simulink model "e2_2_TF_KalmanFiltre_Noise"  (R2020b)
settings: Solver=ode4  StartTime=0.0  StopTime=100  FixedStep=sampleTime  RelTol=1e-3  EnableMultiTasking=on
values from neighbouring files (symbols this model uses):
  gain_noise = 0.25    [startSimulation.m]
  k_d_x = 0.7    [startSimulation.m]
  k_d_y = 0.7    [startSimulation.m]
  k_d_yaw = 0.05    [startSimulation.m]
  k_d_z = 0.05    [startSimulation.m]
  k_i_x = 0.01    [startSimulation.m]
  k_i_y = 0.01    [startSimulation.m]
  k_i_yaw = 0.01    [startSimulation.m]
  k_i_z = 0.01    [startSimulation.m]
  k_p_x = 1    [startSimulation.m]
  k_p_y = 1    [startSimulation.m]
  k_p_yaw = 2    [startSimulation.m]
  k_p_z = 3    [startSimulation.m]
  saturation_psi = 2    [startSimulation.m]
  saturation_x = 2    [startSimulation.m]
  saturation_y = 2    [startSimulation.m]
  saturation_z = 2    [startSimulation.m]
  simDT = 0.01    [startSimulation.m]
undefined symbols (not defined in the file or in its folder): DiscIntNeverNeededParam, KiRollAttitude, sigbuilder_block, unidrnd
libraries: simulink x12, pid_lib x2, aerolibanimutils x1

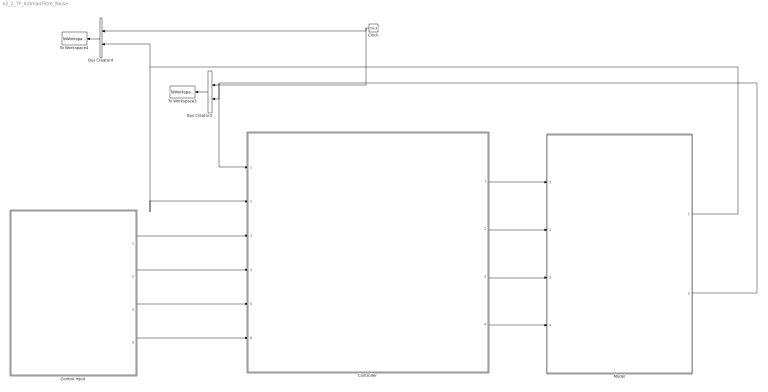
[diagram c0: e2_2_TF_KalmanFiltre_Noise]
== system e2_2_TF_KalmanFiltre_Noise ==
  Bus Creator3 : BusCreator  Inputs=2
  Bus Creator4 : BusCreator  Inputs=2
  Clock : Clock
  Control Input : Subsystem
  "Controller " : Subsystem
  Model : Subsystem
  To Workspace3 : ToWorkspace  VariableName=r1_pos_array  SampleTime=-1
  To Workspace4 : ToWorkspace  VariableName=r1_vel_array  SampleTime=-1
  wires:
  Clock/1 -> Bus Creator4/1, Bus Creator3/1
  Bus Creator3/1 -> To Workspace3/1
  Bus Creator4/1 -> To Workspace4/1
  "Controller "/1(Controller Output X) -> Model/1(Commande Input X)
  "Controller "/2(Controller Output Y) -> Model/2(Commande Input Y)
  "Controller "/3(Controller Output H) -> Model/3(Commande Input H)
  "Controller "/4(Controller Output Psi) -> Model/4(Commande Input Psi)
  Control Input/1(ux) -> "Controller "/3(Control input X)
  Control Input/2(uy) -> "Controller "/4(Control input Y)
  Control Input/3(uz) -> "Controller "/5(Control input H)
  Control Input/4(upsi) -> "Controller "/6(Control input Psi)
  Model/2(Output Position) -> "Controller "/1(Feedback Position), Bus Creator3/2
  Model/1(Output Velocity) -> "Controller "/2(Feedback Velocity), Bus Creator4/2

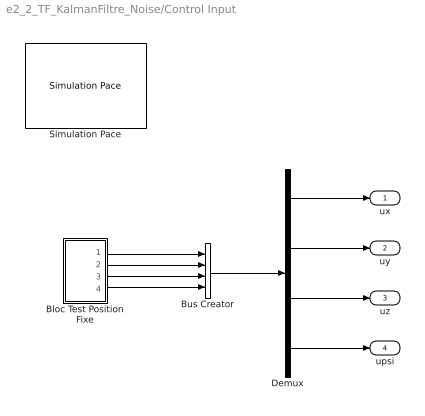
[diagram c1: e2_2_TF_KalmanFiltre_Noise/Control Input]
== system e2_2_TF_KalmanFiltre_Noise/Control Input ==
  Bloc Test Position Fixe : Subsystem
  Bus Creator : BusCreator  Inputs=4
  Demux : Demux
  Simulation Pace : aerolibanimutils/Simulation Pace  SimulationPace=100  SleepMode=MATLAB Thread  OutputPaceError=off  SampleTime=-1
  ux : Outport  VectorParamsAs1DForOutWhenUnconnected=off
  uy : Outport  Port=2  VectorParamsAs1DForOutWhenUnconnected=off
  uz : Outport  Port=3  VectorParamsAs1DForOutWhenUnconnected=off
  upsi : Outport  Port=4  VectorParamsAs1DForOutWhenUnconnected=off
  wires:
  Demux/2 -> uy/1
  Demux/1 -> ux/1
  Bloc Test Position Fixe/2(uy) -> Bus Creator/2
  Demux/3 -> uz/1
  Demux/4 -> upsi/1
  Bloc Test Position Fixe/4(upsi) -> Bus Creator/4
  Bloc Test Position Fixe/3(uz) -> Bus Creator/3
  Bloc Test Position Fixe/1(ux) -> Bus Creator/1
  Bus Creator/1 -> Demux/1

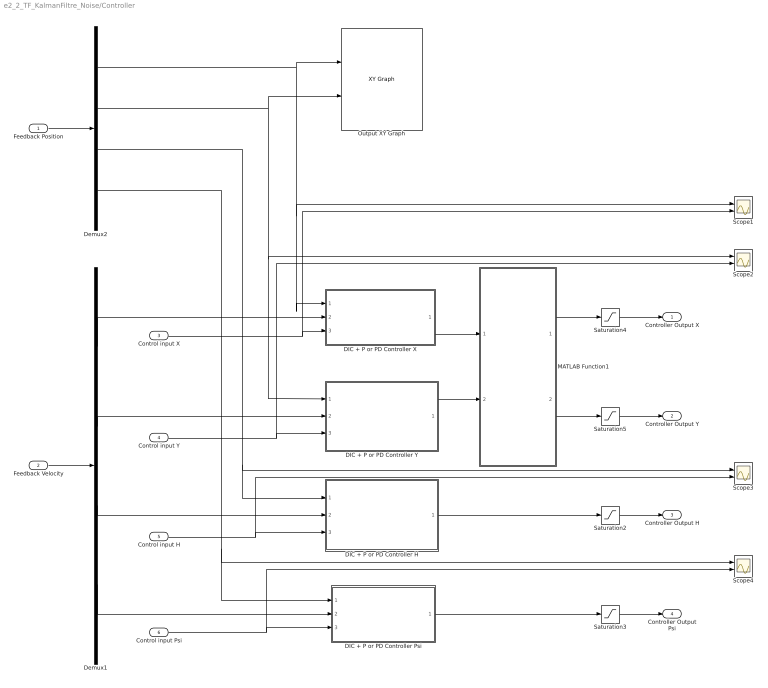
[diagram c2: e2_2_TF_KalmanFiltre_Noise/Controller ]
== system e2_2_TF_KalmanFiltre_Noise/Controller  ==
  Feedback Position : Inport
  Feedback Velocity : Inport  Port=2
  Control input X : Inport  Port=3
  Control input Y : Inport  Port=4
  Control input H : Inport  Port=5
  Control input Psi : Inport  Port=6
  DIC + P or PD Controller H : Subsystem
  DIC + P or PD Controller Psi : Subsystem
  DIC + P or PD Controller X : Subsystem
  DIC + P or PD Controller Y : Subsystem
  Demux1 : Demux
  Demux2 : Demux
  MATLAB Function1 : MATLAB Function  TreatAsAtomicUnit=on
  Output XY Graph : simulink/Sinks/XY Graph  Commented=on  xmin=-5  xmax=5  ymin=-5  ymax=5  st=-1
  Saturation2 : Saturate  UpperLimit=saturation_z  LowerLimit=-saturation_z
  Saturation3 : Saturate  UpperLimit=saturation_psi  LowerLimit=-saturation_psi
  Saturation4 : Saturate  UpperLimit=saturation_x  LowerLimit=-saturation_x
  Saturation5 : Saturate  UpperLimit=saturation_y  LowerLimit=-saturation_y
  Scope{1..4} (4 alike) : Scope  NumInputPorts=2
  Controller Output X : Outport  VectorParamsAs1DForOutWhenUnconnected=off
  Controller Output Y : Outport  Port=2  VectorParamsAs1DForOutWhenUnconnected=off
  Controller Output H : Outport  Port=3  VectorParamsAs1DForOutWhenUnconnected=off
  Controller Output Psi : Outport  Port=4  VectorParamsAs1DForOutWhenUnconnected=off
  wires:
  Feedback Position/1 -> Demux2/1
  Feedback Velocity/1 -> Demux1/1
  Demux1/2 -> DIC + P or PD Controller Y/2(Feedback Velocity Y)
  Demux2/3 -> Scope3/1, DIC + P or PD Controller H/1(Feedback Position H)
  Demux1/1 -> DIC + P or PD Controller X/2(Feedback Velocity X)
  Demux1/3 -> DIC + P or PD Controller H/2(Feedback Velocity H)
  Control input X/1 -> Scope1/2, DIC + P or PD Controller X/3(Control Input X)
  Control input H/1 -> Scope3/2, DIC + P or PD Controller H/3(Control Input H)
  Saturation4/1 -> Controller Output X/1
  Saturation5/1 -> Controller Output Y/1
  Saturation2/1 -> Controller Output H/1
  Saturation3/1 -> Controller Output Psi/1
  Control input Y/1 -> Scope2/2, DIC + P or PD Controller Y/3(Control Input Y)
  DIC + P or PD Controller H/1(Controller Output H) -> Saturation2/1
  DIC + P or PD Controller Psi/1(Controller Output Psi) -> Saturation3/1
  Demux2/1 -> Scope1/1, DIC + P or PD Controller X/1(Feedback Position X), Output XY Graph/1
  Demux2/2 -> Scope2/1, DIC + P or PD Controller Y/1(Feedback Position Y), Output XY Graph/2
  Demux2/4 -> Scope4/1, DIC + P or PD Controller Psi/1(Feedback Position Psi)
  Demux1/4 -> DIC + P or PD Controller Psi/2(Feedback Velocity Psi)
  Control input Psi/1 -> Scope4/2, DIC + P or PD Controller Psi/3(Control input Psi)
  MATLAB Function1/2(phi) -> Saturation5/1
  MATLAB Function1/1(theta) -> Saturation4/1
  DIC + P or PD Controller X/1(Controller Output X) -> MATLAB Function1/1(eax)
  DIC + P or PD Controller Y/1(Controller Output Y) -> MATLAB Function1/2(eay)

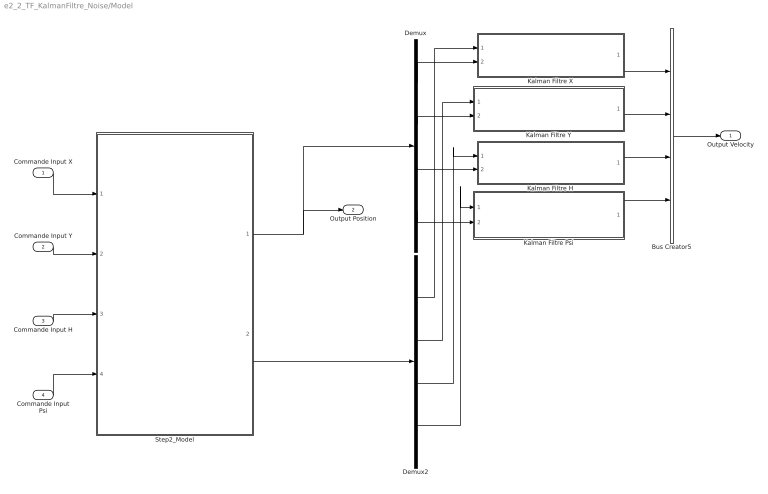
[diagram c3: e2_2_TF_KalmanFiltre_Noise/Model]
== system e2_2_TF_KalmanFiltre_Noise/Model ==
  Commande Input X : Inport
  Commande Input Y : Inport  Port=2
  Commande Input H : Inport  Port=3
  Commande Input Psi : Inport  Port=4
  Bus Creator5 : BusCreator  Inputs=4
  Demux : Demux
  Demux2 : Demux
  Kalman Filtre H : Subsystem
  Kalman Filtre Psi : Subsystem
  Kalman Filtre X : Subsystem
  Kalman Filtre Y : Subsystem
  Step2_Model : Subsystem
  Output Velocity : Outport  VectorParamsAs1DForOutWhenUnconnected=off
  Output Position : Outport  Port=2  VectorParamsAs1DForOutWhenUnconnected=off
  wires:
  Demux2/2 -> Kalman Filtre Y/1(The system output: Velocity)
  Demux/4 -> Kalman Filtre Psi/2(The system output: Position)
  Demux2/4 -> Kalman Filtre Psi/1(The system output: Velocity)
  Demux2/3 -> Kalman Filtre H/1(The system output: Velocity)
  Kalman Filtre H/1(Out velocity feedback) -> Bus Creator5/3
  Kalman Filtre Y/1(Out velocity feedback) -> Bus Creator5/2
  Kalman Filtre Psi/1(Out velocity feedback) -> Bus Creator5/4
  Demux/2 -> Kalman Filtre Y/2(The system output: Position)
  Demux2/1 -> Kalman Filtre X/1(The system output: Velocity)
  Kalman Filtre X/1(Out velocity feedback) -> Bus Creator5/1
  Demux/3 -> Kalman Filtre H/2(The system output: Position)
  Bus Creator5/1 -> Output Velocity/1
  Demux/1 -> Kalman Filtre X/2(The system output: Position)
  Commande Input H/1 -> Step2_Model/3(In3)
  Step2_Model/1(Position) -> Demux/1, Output Position/1
  Commande Input Psi/1 -> Step2_Model/4(In4)
  Commande Input X/1 -> Step2_Model/1(In1)
  Commande Input Y/1 -> Step2_Model/2(In2)
  Step2_Model/2(Velocity) -> Demux2/1

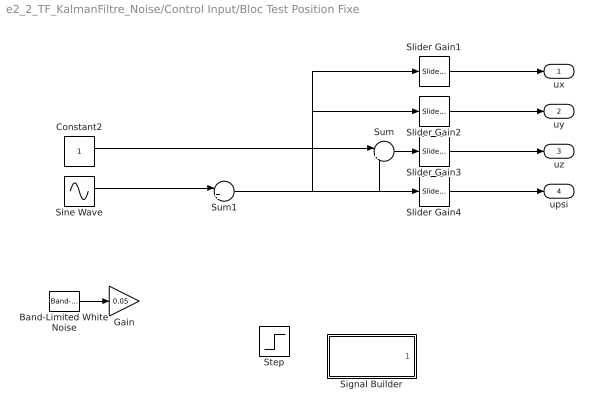
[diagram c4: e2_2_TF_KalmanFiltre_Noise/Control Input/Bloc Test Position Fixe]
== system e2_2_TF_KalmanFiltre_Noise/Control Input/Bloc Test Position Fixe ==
  Band-Limited White Noise : simulink/Sources/Band-Limited White Noise  Cov=[0.01]  Ts=simDT  seed=unidrnd(20000)
  Constant2 : Constant
  Gain : Gain  Gain=0.05
  Signal Builder : Subsystem  Tag=STV Subsys  LoadFcn=sigbuilder_block('load');  StartFcn=sigbuilder_block('start');  StopFcn=sigbuilder_block('stop');  ClipboardFcn=sigbuilder_block('clipboard');  mask(Sigbuilder block){tuvar=[0:10]}
      mask help: Simulink:masks:SigbuilderBlock_MD
      mask init:
      | if ~strcmp(get_param(bdroot(gcbh),'SimulationStatus'),'stopped') tuvar = sigbuilder_block('maskInit'); end
  Sine Wave : Sin  Frequency=0.3  SampleTime=0
  Slider Gain1 : simulink/Math Operations/Slider Gain  gain=1  low=-10  high=10
  Slider Gain2 : simulink/Math Operations/Slider Gain  gain=0  low=-10  high=10
  Slider Gain3 : simulink/Math Operations/Slider Gain  gain=1  low=-2  high=2
  Slider Gain4 : simulink/Math Operations/Slider Gain  gain=1  low=-2  high=2
  Step : Step  Time=5  SampleTime=0
  Sum : Sum  Inputs=|++
  Sum1 : Sum  Inputs=|++
  ux : Outport  VectorParamsAs1DForOutWhenUnconnected=off
  uy : Outport  Port=2  VectorParamsAs1DForOutWhenUnconnected=off
  uz : Outport  Port=3  VectorParamsAs1DForOutWhenUnconnected=off
  upsi : Outport  Port=4  VectorParamsAs1DForOutWhenUnconnected=off
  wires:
  Slider Gain1/1 -> ux/1
  Slider Gain2/1 -> uy/1
  Slider Gain3/1 -> uz/1
  Slider Gain4/1 -> upsi/1
  Sum/1 -> Slider Gain3/1
  Band-Limited White Noise/1 -> Gain/1
  Sine Wave/1 -> Sum1/1
  Sum1/1 -> Slider Gain1/1, Slider Gain2/1, Slider Gain4/1, Sum/2
  Constant2/1 -> Sum/1

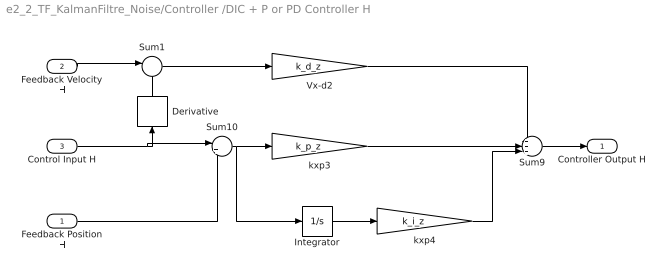
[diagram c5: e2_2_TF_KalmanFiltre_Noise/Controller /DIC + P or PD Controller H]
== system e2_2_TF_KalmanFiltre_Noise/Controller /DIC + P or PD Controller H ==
  Feedback Position H : Inport
  Feedback Velocity H : Inport  Port=2
  Control Input H : Inport  Port=3
  Derivative : Derivative
  Integrator : Integrator
  Sum1 : Sum  Inputs=|-+
  Sum10 : Sum  Inputs=|+-
  Sum9 : Sum  Inputs=+++|
  Vx-d2 : Gain  Gain=k_d_z
  kxp3 : Gain  Gain=k_p_z
  kxp4 : Gain  Gain=k_i_z
  Controller Output H : Outport  VectorParamsAs1DForOutWhenUnconnected=off
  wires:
  Sum9/1 -> Controller Output H/1
  Sum10/1 -> kxp3/1, Integrator/1
  kxp3/1 -> Sum9/2
  Vx-d2/1 -> Sum9/1
  Feedback Velocity H/1 -> Sum1/1
  Sum1/1 -> Vx-d2/1
  Integrator/1 -> kxp4/1
  kxp4/1 -> Sum9/3
  Control Input H/1 -> Sum10/1, Derivative/1
  Feedback Position H/1 -> Sum10/2
  Derivative/1 -> Sum1/2

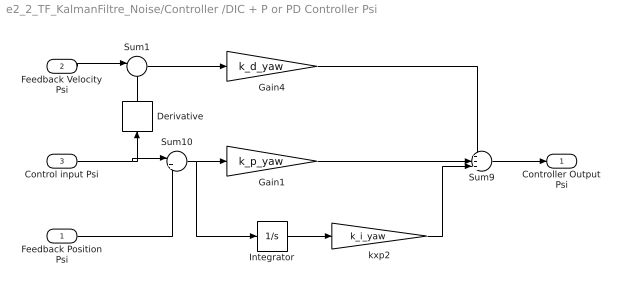
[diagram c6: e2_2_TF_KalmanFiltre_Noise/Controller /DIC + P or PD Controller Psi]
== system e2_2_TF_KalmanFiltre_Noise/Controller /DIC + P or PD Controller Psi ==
  Feedback Position Psi : Inport
  Feedback Velocity Psi : Inport  Port=2
  Control input Psi : Inport  Port=3
  Derivative : Derivative
  Gain1 : Gain  Gain=k_p_yaw
  Gain4 : Gain  Gain=k_d_yaw
  Integrator : Integrator
  Sum1 : Sum  Inputs=|-+
  Sum10 : Sum  Inputs=|+-
  Sum9 : Sum  Inputs=+++|
  kxp2 : Gain  Gain=k_i_yaw
  Controller Output Psi : Outport  VectorParamsAs1DForOutWhenUnconnected=off
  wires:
  Sum9/1 -> Controller Output Psi/1
  kxp2/1 -> Sum9/3
  Control input Psi/1 -> Sum10/1, Derivative/1
  Gain4/1 -> Sum9/1
  Sum10/1 -> Gain1/1, Integrator/1
  Integrator/1 -> kxp2/1
  Feedback Velocity Psi/1 -> Sum1/1
  Sum1/1 -> Gain4/1
  Gain1/1 -> Sum9/2
  Derivative/1 -> Sum1/2
  Feedback Position Psi/1 -> Sum10/2

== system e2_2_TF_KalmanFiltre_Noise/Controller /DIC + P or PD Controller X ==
  Feedback Position X : Inport
  Feedback Velocity X : Inport  Port=2
  Control Input X : Inport  Port=3
  PID1 : Subsystem
  Sum3 : Sum  Inputs=|+-
  Sum4 : Sum  Inputs=|+-
  roll_attitude2 : pid_lib/PID Controller  Controller=P  Form=Parallel  TimeDomain=Discrete-time  UseExternalTs=off  SampleTime=-1  IntegratorMethod=Forward Euler  FilterMethod=Forward Euler  ControllerParametersSource=internal  P=1  I=KiRollAttitude  D=0.01  UseFilter=on  N=100  TunerSelectOption=Transfer Function Based (PID Tuner App)  InitialConditionSource=internal  InitialConditionForIntegrator=0  InitialConditionForFilter=0  DifferentiatorICPrevScaledInput=0  ExternalReset=none  TrackingMode=off  Kt=1  LimitOutput=on  SatLimitsSource=internal  UpperSaturationLimit=100  LowerSaturationLimit=-100  LinearizeAsGain=on  AntiWindupMode=back-calculation  Kb=1  POutMin=[]  POutMax=[]  IOutMin=[]  IOutMax=[]  DOutMin=[]  DOutMax=[]  NOutMin=[]  NOutMax=[]  SumOutMin=[]  SumOutMax=[]  SaturationOutMin=[]  SaturationOutMax=[]  PParamMin=[]  PParamMax=[]  IParamMin=[]  IParamMax=[]  DParamMin=[]  DParamMax=[]  NParamMin=[]  NParamMax=[]  KbParamMin=[]  KbParamMax=[]  KtParamMin=[]  KtParamMax=[]  KbOutMin=[]  KbOutMax=[]  KtOutMin=[]  KtOutMax=[]  IntegratorOutMin=[]  IntegratorOutMax=[]  FilterOutMin=[]  FilterOutMax=[]  SumI1OutMin=[]  SumI1OutMax=[]  SumI2OutMin=[]  SumI2OutMax=[]  SumI3OutMin=[]  SumI3OutMax=[]  SumI4OutMin=[]  SumI4OutMax=[]  SumDOutMin=[]  SumDOutMax=[]  DifferentiatorOutMin=[]  DifferentiatorOutMax=[]  FilterDiffOutCoefMin=[]  FilterDiffOutCoefMax=[]  ReciprocalOutMin=[]  ReciprocalOutMax=[]  SumDenOutMin=[]  SumDenOutMax=[]  SumNumOutMin=[]  SumNumOutMax=[]  DivideOutMin=[]  DivideOutMax=[]  UdiffTsProdOutMin=[]  UdiffTsProdOutMax=[]  NTsProdOutMin=[]  NTsProdOutMax=[]  UintegralTsProdOutMin=[]  UintegralTsProdOutMax=[]  UngainTsProdOutMin=[]  UngainTsProdOutMax=[]  IntegratorContinuousStateAttributes=''  IntegratorStateMustResolveToSignalObject=off  IntegratorRTWStateStorageClass=Auto  FilterContinuousStateAttributes=''  FilterStateMustResolveToSignalObject=off  FilterRTWStateStorageClass=Auto  ParallelPVariant=InternalParameters  IdealPVariant=Disabled  IVariant=Disabled  DVariant=Disabled  IntegratorVariant=Disabled  SatVariant=Enabled  AWVariant=Disabled  PCopyVariant=Disabled  TRVariant=Disabled  FdbkBlocksVariant=Forward  IdealPFdbkVariant=Disabled  SatFdbkVariant=Disabled  DerivativeFilterVariant=Disabled  NVariant=Disabled  NCopyVariant=Disabled_SignalSpec  FilterICVariant=Disabled  IntegratorICVariant=Disabled  ExternalResetVariant=Disabled  TRSumVariant=Passthrough  SumFdbkVariant=Disabled  SumVariant=Passthrough_P  TsampFilterVariant=InternalTs  TsampNgainVariant=Passthrough  TsampIntegralVariant=Disabled_SignalSpec  ExternalSaturationOutDataTypeStr=Inherit: Same as second input
  Controller Output X : Outport  VectorParamsAs1DForOutWhenUnconnected=off
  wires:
  roll_attitude2/1 -> Sum4/1
  Sum3/1 -> roll_attitude2/1
  Sum4/1 -> PID1/1(x)
  PID1/1(y) -> Controller Output X/1
  Feedback Velocity X/1 -> Sum4/2
  Control Input X/1 -> Sum3/1
  Feedback Position X/1 -> Sum3/2

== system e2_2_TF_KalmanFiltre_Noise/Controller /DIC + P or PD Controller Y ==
  Feedback Position Y : Inport
  Feedback Velocity Y : Inport  Port=2
  Control Input Y : Inport  Port=3
  PID2 : Subsystem
  Sum : Sum  Inputs=|+-
  Sum2 : Sum  Inputs=|+-
  roll_attitude : pid_lib/PID Controller  Controller=P  Form=Parallel  TimeDomain=Discrete-time  UseExternalTs=off  SampleTime=-1  IntegratorMethod=Forward Euler  FilterMethod=Forward Euler  ControllerParametersSource=internal  P=1  I=KiRollAttitude  D=0.01  UseFilter=on  N=100  TunerSelectOption=Transfer Function Based (PID Tuner App)  InitialConditionSource=internal  InitialConditionForIntegrator=0  InitialConditionForFilter=0  DifferentiatorICPrevScaledInput=0  ExternalReset=none  TrackingMode=off  Kt=1  LimitOutput=on  SatLimitsSource=internal  UpperSaturationLimit=1  LowerSaturationLimit=-1  LinearizeAsGain=on  AntiWindupMode=back-calculation  Kb=1  POutMin=[]  POutMax=[]  IOutMin=[]  IOutMax=[]  DOutMin=[]  DOutMax=[]  NOutMin=[]  NOutMax=[]  SumOutMin=[]  SumOutMax=[]  SaturationOutMin=[]  SaturationOutMax=[]  PParamMin=[]  PParamMax=[]  IParamMin=[]  IParamMax=[]  DParamMin=[]  DParamMax=[]  NParamMin=[]  NParamMax=[]  KbParamMin=[]  KbParamMax=[]  KtParamMin=[]  KtParamMax=[]  KbOutMin=[]  KbOutMax=[]  KtOutMin=[]  KtOutMax=[]  IntegratorOutMin=[]  IntegratorOutMax=[]  FilterOutMin=[]  FilterOutMax=[]  SumI1OutMin=[]  SumI1OutMax=[]  SumI2OutMin=[]  SumI2OutMax=[]  SumI3OutMin=[]  SumI3OutMax=[]  SumI4OutMin=[]  SumI4OutMax=[]  SumDOutMin=[]  SumDOutMax=[]  DifferentiatorOutMin=[]  DifferentiatorOutMax=[]  FilterDiffOutCoefMin=[]  FilterDiffOutCoefMax=[]  ReciprocalOutMin=[]  ReciprocalOutMax=[]  SumDenOutMin=[]  SumDenOutMax=[]  SumNumOutMin=[]  SumNumOutMax=[]  DivideOutMin=[]  DivideOutMax=[]  UdiffTsProdOutMin=[]  UdiffTsProdOutMax=[]  NTsProdOutMin=[]  NTsProdOutMax=[]  UintegralTsProdOutMin=[]  UintegralTsProdOutMax=[]  UngainTsProdOutMin=[]  UngainTsProdOutMax=[]  IntegratorContinuousStateAttributes=''  IntegratorStateMustResolveToSignalObject=off  IntegratorRTWStateStorageClass=Auto  FilterContinuousStateAttributes=''  FilterStateMustResolveToSignalObject=off  FilterRTWStateStorageClass=Auto  ParallelPVariant=InternalParameters  IdealPVariant=Disabled  IVariant=Disabled  DVariant=Disabled  IntegratorVariant=Disabled  SatVariant=Enabled  AWVariant=Disabled  PCopyVariant=Disabled  TRVariant=Disabled  FdbkBlocksVariant=Forward  IdealPFdbkVariant=Disabled  SatFdbkVariant=Disabled  DerivativeFilterVariant=Disabled  NVariant=Disabled  NCopyVariant=Disabled_SignalSpec  FilterICVariant=Disabled  IntegratorICVariant=Disabled  ExternalResetVariant=Disabled  TRSumVariant=Passthrough  SumFdbkVariant=Disabled  SumVariant=Passthrough_P  TsampFilterVariant=InternalTs  TsampNgainVariant=Passthrough  TsampIntegralVariant=Disabled_SignalSpec  ExternalSaturationOutDataTypeStr=Inherit: Same as second input
  Controller Output Y : Outport  VectorParamsAs1DForOutWhenUnconnected=off
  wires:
  Sum/1 -> roll_attitude/1
  roll_attitude/1 -> Sum2/1
  Sum2/1 -> PID2/1(x)
  Feedback Position Y/1 -> Sum/2
  Feedback Velocity Y/1 -> Sum2/2
  Control Input Y/1 -> Sum/1
  PID2/1(y) -> Controller Output Y/1

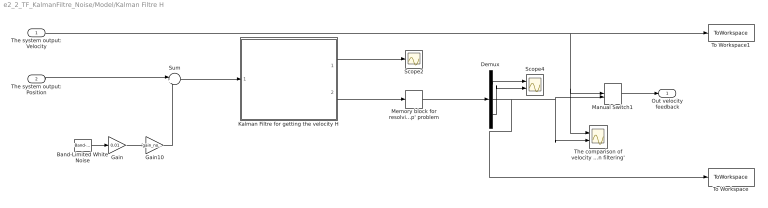
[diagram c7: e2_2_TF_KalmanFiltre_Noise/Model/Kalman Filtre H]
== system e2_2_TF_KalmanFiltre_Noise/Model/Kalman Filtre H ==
  The system output: Velocity : Inport
  The system output: Position : Inport  Port=2
  Band-Limited White Noise : simulink/Sources/Band-Limited White Noise  Cov=[0.01]  Ts=simDT  seed=unidrnd(20000)
  Demux : Demux  Outputs=3
  Gain : Gain  Gain=0.01
  Gain10 : Gain  Gain=gain_noise
  Kalman Filtre for getting the velocity H : MATLAB Function  TreatAsAtomicUnit=on  SystemSampleTime=0.01
  Manual Switch1 : ManualSwitch  CurrentSetting=0
  Memory block for resolving the 'algebraic loop' problem : Memory
  Scope2 : Scope
  Scope4 : Scope  NumInputPorts=2
  Sum : Sum  Inputs=|++
  The comparison of velocity signal between 'Derivative' and 'Kalman filtering' : Scope  NumInputPorts=2
  To Workspace : ToWorkspace  VariableName=vh_kalman  SampleTime=-1
  To Workspace1 : ToWorkspace  VariableName=vh_real  SampleTime=-1
  Out velocity feedback : Outport  VectorParamsAs1DForOutWhenUnconnected=off
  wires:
  Manual Switch1/1 -> Out velocity feedback/1
  Memory block for resolving the 'algebraic loop' problem/1 -> Demux/1
  Kalman Filtre for getting the velocity H/1(Covariance_matrice) -> Scope2/1
  Demux/1 -> Scope4/1
  Kalman Filtre for getting the velocity H/2(X_Kalmanfiltred) -> Memory block for resolving the 'algebraic loop' problem/1
  Demux/2 -> To Workspace/1, The comparison of velocity signal between 'Derivative' and 'Kalman filtering'/2, Manual Switch1/2
  Demux/3 -> Scope4/2
  The system output: Velocity/1 -> To Workspace1/1, The comparison of velocity signal between 'Derivative' and 'Kalman filtering'/1, Manual Switch1/1
  Gain10/1 -> Sum/2
  Band-Limited White Noise/1 -> Gain/1
  Gain/1 -> Gain10/1
  The system output: Position/1 -> Sum/1
  Sum/1 -> Kalman Filtre for getting the velocity H/1(Mesurement_Velocity)

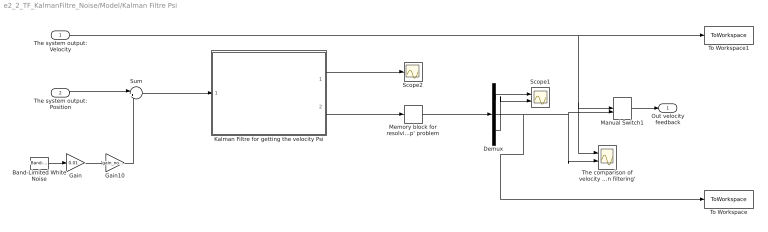
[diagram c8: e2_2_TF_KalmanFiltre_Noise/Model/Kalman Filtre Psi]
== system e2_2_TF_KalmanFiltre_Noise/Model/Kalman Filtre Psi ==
  The system output: Velocity : Inport
  The system output: Position : Inport  Port=2
  Band-Limited White Noise : simulink/Sources/Band-Limited White Noise  Cov=[0.01]  Ts=simDT  seed=unidrnd(20000)
  Demux : Demux  Outputs=3
  Gain : Gain  Gain=0.01
  Gain10 : Gain  Gain=gain_noise
  Kalman Filtre for getting the velocity Psi : MATLAB Function  TreatAsAtomicUnit=on  SystemSampleTime=0.01
  Manual Switch1 : ManualSwitch  CurrentSetting=0
  Memory block for resolving the 'algebraic loop' problem : Memory
  Scope1 : Scope  NumInputPorts=2
  Scope2 : Scope
  Sum : Sum  Inputs=|++
  The comparison of velocity signal between 'Derivative' and 'Kalman filtering' : Scope  NumInputPorts=2
  To Workspace : ToWorkspace  VariableName=vpsi_kalman  SampleTime=-1
  To Workspace1 : ToWorkspace  VariableName=vpsi_real  SampleTime=-1
  Out velocity feedback : Outport  VectorParamsAs1DForOutWhenUnconnected=off
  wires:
  Manual Switch1/1 -> Out velocity feedback/1
  Memory block for resolving the 'algebraic loop' problem/1 -> Demux/1
  Kalman Filtre for getting the velocity Psi/1(Covariance_matrice) -> Scope2/1
  Kalman Filtre for getting the velocity Psi/2(X_Kalmanfiltred) -> Memory block for resolving the 'algebraic loop' problem/1
  Demux/2 -> To Workspace/1, The comparison of velocity signal between 'Derivative' and 'Kalman filtering'/2, Manual Switch1/2
  Demux/1 -> Scope1/1
  Demux/3 -> Scope1/2
  The system output: Velocity/1 -> To Workspace1/1, The comparison of velocity signal between 'Derivative' and 'Kalman filtering'/1, Manual Switch1/1
  Sum/1 -> Kalman Filtre for getting the velocity Psi/1(Mesurement_Velocity)
  The system output: Position/1 -> Sum/1
  Gain10/1 -> Sum/2
  Band-Limited White Noise/1 -> Gain/1
  Gain/1 -> Gain10/1

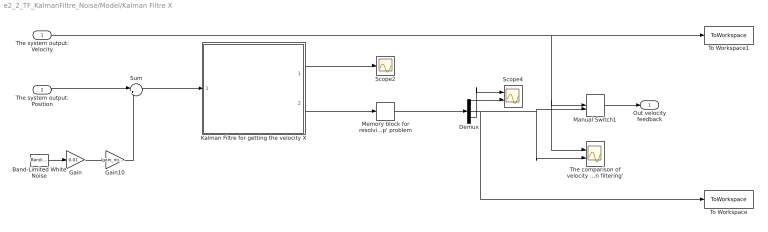
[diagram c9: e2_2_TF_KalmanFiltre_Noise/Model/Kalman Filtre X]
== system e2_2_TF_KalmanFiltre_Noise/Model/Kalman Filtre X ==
  The system output: Velocity : Inport
  The system output: Position : Inport  Port=2
  Band-Limited White Noise : simulink/Sources/Band-Limited White Noise  Cov=[0.01]  Ts=simDT  seed=unidrnd(20000)
  Demux : Demux  Outputs=3
  Gain : Gain  Gain=0.01
  Gain10 : Gain  Gain=gain_noise
  Kalman Filtre for getting the velocity X : MATLAB Function  TreatAsAtomicUnit=on  SystemSampleTime=0.01
  Manual Switch1 : ManualSwitch  CurrentSetting=0
  Memory block for resolving the 'algebraic loop' problem : Memory
  Scope2 : Scope
  Scope4 : Scope  NumInputPorts=2
  Sum : Sum  Inputs=|++
  The comparison of velocity signal between 'Derivative' and 'Kalman filtering' : Scope  NumInputPorts=2
  To Workspace : ToWorkspace  VariableName=vx_kalman  SampleTime=-1
  To Workspace1 : ToWorkspace  VariableName=vx_real  SampleTime=-1
  Out velocity feedback : Outport  VectorParamsAs1DForOutWhenUnconnected=off
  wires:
  Kalman Filtre for getting the velocity X/1(Covariance_matrice) -> Scope2/1
  Kalman Filtre for getting the velocity X/2(X_Kalmanfiltred) -> Memory block for resolving the 'algebraic loop' problem/1
  Memory block for resolving the 'algebraic loop' problem/1 -> Demux/1
  Manual Switch1/1 -> Out velocity feedback/1
  Demux/2 -> To Workspace/1, The comparison of velocity signal between 'Derivative' and 'Kalman filtering'/2, Manual Switch1/2
  Demux/1 -> Scope4/2
  Demux/3 -> Scope4/1
  The system output: Velocity/1 -> The comparison of velocity signal between 'Derivative' and 'Kalman filtering'/1, Manual Switch1/1, To Workspace1/1
  Gain10/1 -> Sum/2
  Band-Limited White Noise/1 -> Gain/1
  Gain/1 -> Gain10/1
  The system output: Position/1 -> Sum/1
  Sum/1 -> Kalman Filtre for getting the velocity X/1(Mesurement_Velocity)

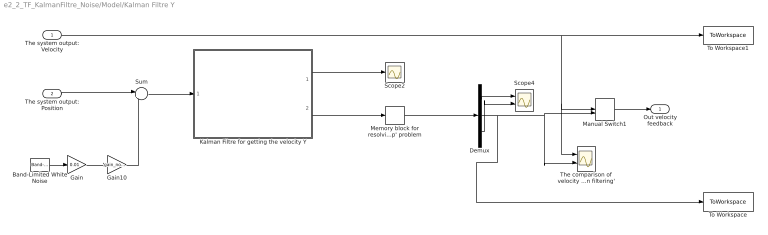
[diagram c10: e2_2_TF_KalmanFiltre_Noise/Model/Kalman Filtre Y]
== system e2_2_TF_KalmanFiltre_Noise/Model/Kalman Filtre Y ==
  The system output: Velocity : Inport
  The system output: Position : Inport  Port=2
  Band-Limited White Noise : simulink/Sources/Band-Limited White Noise  Cov=[0.01]  Ts=simDT  seed=unidrnd(20000)
  Demux : Demux  Outputs=3
  Gain : Gain  Gain=0.01
  Gain10 : Gain  Gain=gain_noise
  Kalman Filtre for getting the velocity Y : MATLAB Function  TreatAsAtomicUnit=on  SystemSampleTime=0.01
  Manual Switch1 : ManualSwitch  CurrentSetting=0
  Memory block for resolving the 'algebraic loop' problem : Memory
  Scope2 : Scope
  Scope4 : Scope  NumInputPorts=2
  Sum : Sum  Inputs=|++
  The comparison of velocity signal between 'Derivative' and 'Kalman filtering' : Scope  NumInputPorts=2
  To Workspace : ToWorkspace  VariableName=vy_kalman  SampleTime=-1
  To Workspace1 : ToWorkspace  VariableName=vy_real  SampleTime=-1
  Out velocity feedback : Outport  VectorParamsAs1DForOutWhenUnconnected=off
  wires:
  Kalman Filtre for getting the velocity Y/2(X_Kalmanfiltred) -> Memory block for resolving the 'algebraic loop' problem/1
  Manual Switch1/1 -> Out velocity feedback/1
  Demux/2 -> To Workspace/1, The comparison of velocity signal between 'Derivative' and 'Kalman filtering'/2, Manual Switch1/2
  Kalman Filtre for getting the velocity Y/1(Covariance_matrice) -> Scope2/1
  Memory block for resolving the 'algebraic loop' problem/1 -> Demux/1
  Demux/1 -> Scope4/1
  Demux/3 -> Scope4/2
  The system output: Velocity/1 -> The comparison of velocity signal between 'Derivative' and 'Kalman filtering'/1, Manual Switch1/1, To Workspace1/1
  Gain10/1 -> Sum/2
  Band-Limited White Noise/1 -> Gain/1
  Gain/1 -> Gain10/1
  The system output: Position/1 -> Sum/1
  Sum/1 -> Kalman Filtre for getting the velocity Y/1(Mesurement_Velocity)

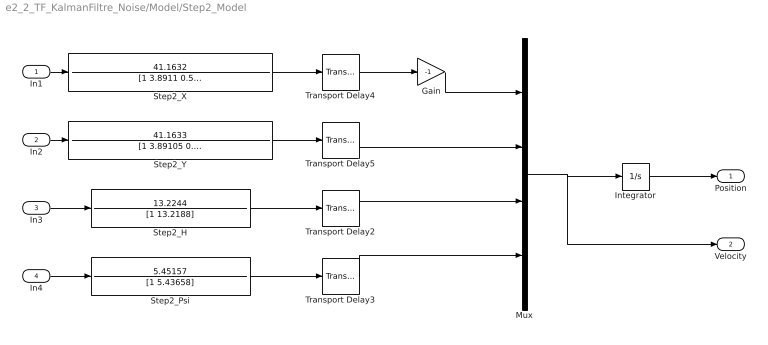
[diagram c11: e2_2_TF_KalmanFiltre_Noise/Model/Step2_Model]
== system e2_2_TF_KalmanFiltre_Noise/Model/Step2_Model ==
  In1 : Inport
  In2 : Inport  Port=2
  In3 : Inport  Port=3
  In4 : Inport  Port=4
  Gain : Gain  Gain=-1
  Integrator : Integrator
  Mux : Mux
  Step2_H : TransferFcn  Numerator=13.2244  Denominator=[1 13.2188]
  Step2_Psi : TransferFcn  Numerator=5.45157  Denominator=[1 5.43658]
  Step2_X : TransferFcn  Numerator=41.1632  Denominator=[1 3.8911 0.529635]
  Step2_Y : TransferFcn  Numerator=41.1633  Denominator=[1 3.89105 0.529839]
  Transport Delay2 : TransportDelay  DelayTime=0.0344
  Transport Delay3 : TransportDelay  DelayTime=0.0313
  Transport Delay4 : TransportDelay  DelayTime=0.0289
  Transport Delay5 : TransportDelay  DelayTime=0.0289
  Position : Outport  VectorParamsAs1DForOutWhenUnconnected=off
  Velocity : Outport  Port=2  VectorParamsAs1DForOutWhenUnconnected=off
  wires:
  Transport Delay2/1 -> Mux/3
  In2/1 -> Step2_Y/1
  In4/1 -> Step2_Psi/1
  Transport Delay3/1 -> Mux/4
  In1/1 -> Step2_X/1
  In3/1 -> Step2_H/1
  Step2_H/1 -> Transport Delay2/1
  Step2_Y/1 -> Transport Delay5/1
  Step2_X/1 -> Transport Delay4/1
  Step2_Psi/1 -> Transport Delay3/1
  Transport Delay4/1 -> Gain/1
  Transport Delay5/1 -> Mux/2
  Integrator/1 -> Position/1
  Mux/1 -> Velocity/1, Integrator/1
  Gain/1 -> Mux/1

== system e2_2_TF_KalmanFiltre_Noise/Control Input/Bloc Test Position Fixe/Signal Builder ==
  Demux : Demux  Tag=STV Demux  Outputs=1
  FromWs : FromWorkspace  Tag=STV FromWs  VariableName=tuvar
  Signal 2 : Outport  Tag=STV Outport  VectorParamsAs1DForOutWhenUnconnected=off
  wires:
  FromWs/1 -> Demux/1
  Demux/1 -> Signal 2/1

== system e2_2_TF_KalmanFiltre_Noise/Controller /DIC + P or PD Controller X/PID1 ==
  x : Inport
  Discrete Derivative : simulink/Discrete/Discrete Derivative  gainval=1.0  ICPrevScaledInput=0.0  OutMin=-5  OutMax=5  OutDataType=fixdt(1, 16)  OutScaling=2^-10  DoSatur=off
  Discrete-Time Integrator : DiscreteIntegrator  SampleTime=-1  LimitOutput=on  UpperSaturationLimit=5  LowerSaturationLimit=-5  ICPrevOutput=DiscIntNeverNeededParam  ICPrevScaledInput=DiscIntNeverNeededParam
  Sum : Sum  Inputs=+++  OutMin=-10  OutMax=10
  Vx-d3 : Gain  Gain=k_d_x
  kxp2 : Gain  Gain=k_i_x
  kxp3 : Gain  Gain=k_p_x
  y : Outport  InitialOutput=0  VectorParamsAs1DForOutWhenUnconnected=off
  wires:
  x/1 -> Vx-d3/1, kxp2/1, kxp3/1
  kxp2/1 -> Discrete-Time Integrator/1
  Vx-d3/1 -> Discrete Derivative/1
  kxp3/1 -> Sum/1
  Sum/1 -> y/1
  Discrete Derivative/1 -> Sum/3
  Discrete-Time Integrator/1 -> Sum/2

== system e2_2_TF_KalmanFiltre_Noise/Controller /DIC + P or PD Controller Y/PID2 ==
  x : Inport
  Discrete Derivative : simulink/Discrete/Discrete Derivative  gainval=1.0  ICPrevScaledInput=0.0  OutMin=[]  OutMax=[]  OutDataType=fixdt(1, 16)  OutScaling=2^-10  DoSatur=off
  Discrete-Time Integrator : DiscreteIntegrator  SampleTime=-1  LimitOutput=on  UpperSaturationLimit=10  LowerSaturationLimit=-10  ICPrevOutput=DiscIntNeverNeededParam  ICPrevScaledInput=DiscIntNeverNeededParam
  Sum : Sum  Inputs=+++  OutMin=-10  OutMax=10
  Vx-d2 : Gain  Gain=k_d_y
  kxp2 : Gain  Gain=k_p_y
  kxp3 : Gain  Gain=k_i_y
  y : Outport  InitialOutput=0  VectorParamsAs1DForOutWhenUnconnected=off
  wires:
  x/1 -> kxp2/1, kxp3/1, Vx-d2/1
  kxp3/1 -> Discrete-Time Integrator/1
  Vx-d2/1 -> Discrete Derivative/1
  kxp2/1 -> Sum/1
  Sum/1 -> y/1
  Discrete Derivative/1 -> Sum/3
  Discrete-Time Integrator/1 -> Sum/2

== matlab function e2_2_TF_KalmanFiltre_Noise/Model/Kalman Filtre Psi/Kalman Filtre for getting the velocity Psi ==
function [Covariance_matrice,X_Kalmanfiltred] = fcn(Mesurement_Velocity)

% Persistent process for saving the last state and initilizing the variable
persistent P0_static;
if isempty(P0_static)
    P0_static=[0.1,0 0;0,0.1,0;0 0 0.1]; % the initilized matrice of estimated error
end

persistent Xkf_static;
if isempty(Xkf_static)
    Xkf_static=[0;0;0]; % the initilized state from Kalman Estimaton
end

% Determine the constants

% Simple time
Ts =0.01;

% Process Noise
p_var =0.1; % sigma   0.3 / 0.1 / 0.05
Q = eye(3)*p_var^2; % the covariance matrice of process noise
W=Q*randn(3,1);  % process noise

% Mesurement Noise
m_var =1; % sigma  
% 0.03 0.6 3 / 0.01 0.2 1 / 0.0025 0.05 0.25
R = [m_var^2 ];  % the covariance matrice of mesurement noise
V=R*randn; % mesurement noise

% Observation matrice
H=[1 0 0];

% The indentity matrice
I=eye(3); 

% State Transition Martrix
A=[1 Ts 0.5*(Ts^2);0 1 Ts;0 0 1];

% Steady-State equation

% persistent X_real_static;
% if isempty(X_real_static)
%     X_real_static=[0;0]; % the initilized state from Kalman Estimaton
% end
% X_real_forward=X_real_static;
% X_real=A*X_real_forward+W;
% Mesurement_Velocity=H*(X_real)+V;
% X_real_static=X_real;    

%   Kalman Update process
    X_pre=A*Xkf_static; % State estimation
    P_pre=A*P0_static*A'+Q; % Covariance matrice estimation

    Kg=P_pre*H'*inv(H*P_pre*H'+R); % Kalman Gain calculation

    X_Kalmanfiltred=X_pre+Kg*(Mesurement_Velocity-H*X_pre); % State estimation update
    Covariance_matrice=(I-Kg*H)*P_pre; % Covariance matrice estimation update

% update the value of the persistent variable for iterating the Kalman process
P0_static=Covariance_matrice;
Xkf_static=X_Kalmanfiltred;

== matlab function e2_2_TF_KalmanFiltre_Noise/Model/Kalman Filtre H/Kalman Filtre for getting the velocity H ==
function [Covariance_matrice,X_Kalmanfiltred] = fcn(Mesurement_Velocity)

% 卡尔曼滤波初始化
persistent P0_static;
if isempty(P0_static)
    P0_static=[0.1,0 0;0,0.1,0;0 0 0.1]; % 初始化误差协方差矩阵
end

persistent Xkf_static;
if isempty(Xkf_static)
    Xkf_static=[0;0;0]; % 卡尔曼滤波估计初始状态
end

% 时间参数

% 仿真步长
Ts =0.01;

% 过程噪声
p_var =0.1 % sigma
Q = eye(3)*p_var^2; % 过程噪声协方差矩阵
W=Q*randn(3,1);  % 过程噪声

% 测量噪声
m_var = 1; % sigma   
R = [m_var^2 ];  % 测量噪声协方差矩阵
V=R*randn; % 测量噪声

% 观测方程矩阵
H=[1 0 0];

% 单位矩阵
I=eye(3); 

% 状态转移矩阵
A=[1 Ts 0.5*(Ts^2);0 1 Ts;0 0 1];

% Steady-State equation

% persistent X_real_static;
% if isempty(X_real_static)
%     X_real_static=[0;0]; % the initilized state from Kalman Estimaton
% end
% X_real_forward=X_real_static;
% X_real=A*X_real_forward+W;
% Mesurement_Velocity=H*(X_real)+V;
% X_real_static=X_real;    

%   Kalman Update process
    X_pre=A*Xkf_static; % State estimation
    P_pre=A*P0_static*A'+Q; % Covariance matrice estimation

    Kg=P_pre*H'*inv(H*P_pre*H'+R); % Kalman Gain calculation

    X_Kalmanfiltred=X_pre+Kg*(Mesurement_Velocity-H*X_pre); % State estimation update
    Covariance_matrice=(I-Kg*H)*P_pre; % Covariance matrice estimation update

% update the value of the persistent variable for iterating the Kalman process
P0_static=Covariance_matrice;
Xkf_static=X_Kalmanfiltred;

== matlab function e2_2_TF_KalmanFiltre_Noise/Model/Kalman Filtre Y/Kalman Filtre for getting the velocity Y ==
function [Covariance_matrice,X_Kalmanfiltred] = fcn(Mesurement_Velocity)

% Persistent process for saving the last state and initilizing the variable
persistent P0_static;
if isempty(P0_static)
    P0_static=[0.1,0 0;0,0.1,0;0 0 0.1]; % the initilized matrice of estimated error
end

persistent Xkf_static;
if isempty(Xkf_static)
    Xkf_static=[0;0;0]; % the initilized state from Kalman Estimaton
end

% Determine the constants

% Simple time
Ts =0.01;

% Process Noise
p_var =0.3; % sigma     0.3 / 0.1 / 0.05
Q = eye(3)*p_var^2; % the covariance matrice of process noise
W=Q*randn(3,1);  % process noise

% Mesurement Noise
m_var = 3; % sigma    
% 0.03 0.6 3 / 0.01 0.2 1 / 0.0025 0.05 0.25
R = [m_var^2 ];  % the covariance matrice of mesurement noise
V=R*randn; % mesurement noise

% Observation matrice
H=[1 0 0];

% The indentity matrice
I=eye(3); 

% State Transition Martrix
A=[1 Ts 0.5*(Ts^2);0 1 Ts;0 0 1];

% Steady-State equation

% persistent X_real_static;
% if isempty(X_real_static)
%     X_real_static=[0;0]; % the initilized state from Kalman Estimaton
% end
% X_real_forward=X_real_static;
% X_real=A*X_real_forward+W;
% Mesurement_Velocity=H*(X_real)+V;
% X_real_static=X_real;    

%   Kalman Update process
    X_pre=A*Xkf_static; % State estimation
    P_pre=A*P0_static*A'+Q; % Covariance matrice estimation

    Kg=P_pre*H'*inv(H*P_pre*H'+R); % Kalman Gain calculation

    X_Kalmanfiltred=X_pre+Kg*(Mesurement_Velocity-H*X_pre); % State estimation update
    Covariance_matrice=(I-Kg*H)*P_pre; % Covariance matrice estimation update

% update the value of the persistent variable for iterating the Kalman process
P0_static=Covariance_matrice;
Xkf_static=X_Kalmanfiltred;

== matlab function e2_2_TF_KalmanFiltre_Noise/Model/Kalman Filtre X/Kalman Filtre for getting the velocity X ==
function [Covariance_matrice,X_Kalmanfiltred] = fcn(Mesurement_Velocity)

% Persistent process for saving the last state and initilizing the variable
persistent P0_static;
if isempty(P0_static)
    P0_static=[0.1,0 0;0,0.1,0;0 0 0.1]; % the initilized matrice of estimated error
end

persistent Xkf_static;
if isempty(Xkf_static)
    Xkf_static=[0;0;0]; % the initilized state from Kalman Estimaton
end

% Determine the constants

% Simple time
Ts =0.01;

% Process Noise
p_var =0.3; % sigma    0.3 / 0.1 / 0.05
Q = eye(3)*p_var^2; % the covariance matrice of process noise
W=Q*randn(3,1);  % process noise

% Mesurement Noise
m_var =0.6; % sigma  
% 0.03 0.6 3 / 0.01 0.2 1 / 0.0025 0.05 0.25
R = [m_var^2 ];  % the covariance matrice of mesurement noise
V=R*randn; % mesurement noise

% Observation matrice
H=[1 0 0];

% The indentity matrice
I=eye(3); 

% State Transition Martrix
A=[1 Ts 0.5*(Ts^2);0 1 Ts;0 0 1];

% Steady-State equation

% persistent X_real_static;
% if isempty(X_real_static)
%     X_real_static=[0;0]; % the initilized state from Kalman Estimaton
% end
% X_real_forward=X_real_static;
% X_real=A*X_real_forward+W;
% Mesurement_Velocity=H*(X_real)+V;
% X_real_static=X_real;    

%   Kalman Update process
    X_pre=A*Xkf_static; % State estimation
    P_pre=A*P0_static*A'+Q; % Covariance matrice estimation

    Kg=P_pre*H'*inv(H*P_pre*H'+R); % Kalman Gain calculation

    X_Kalmanfiltred=X_pre+Kg*(Mesurement_Velocity-H*X_pre); % State estimation update
    Covariance_matrice=(I-Kg*H)*P_pre; % Covariance matrice estimation update

% update the value of the persistent variable for iterating the Kalman process
P0_static=Covariance_matrice;
Xkf_static=X_Kalmanfiltred;

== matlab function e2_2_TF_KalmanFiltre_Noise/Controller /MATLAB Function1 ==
function [theta,phi] = fcn(eax,eay)
g=9.8;

theta =-eax/g;% vx
phi =eay/g;% vy
